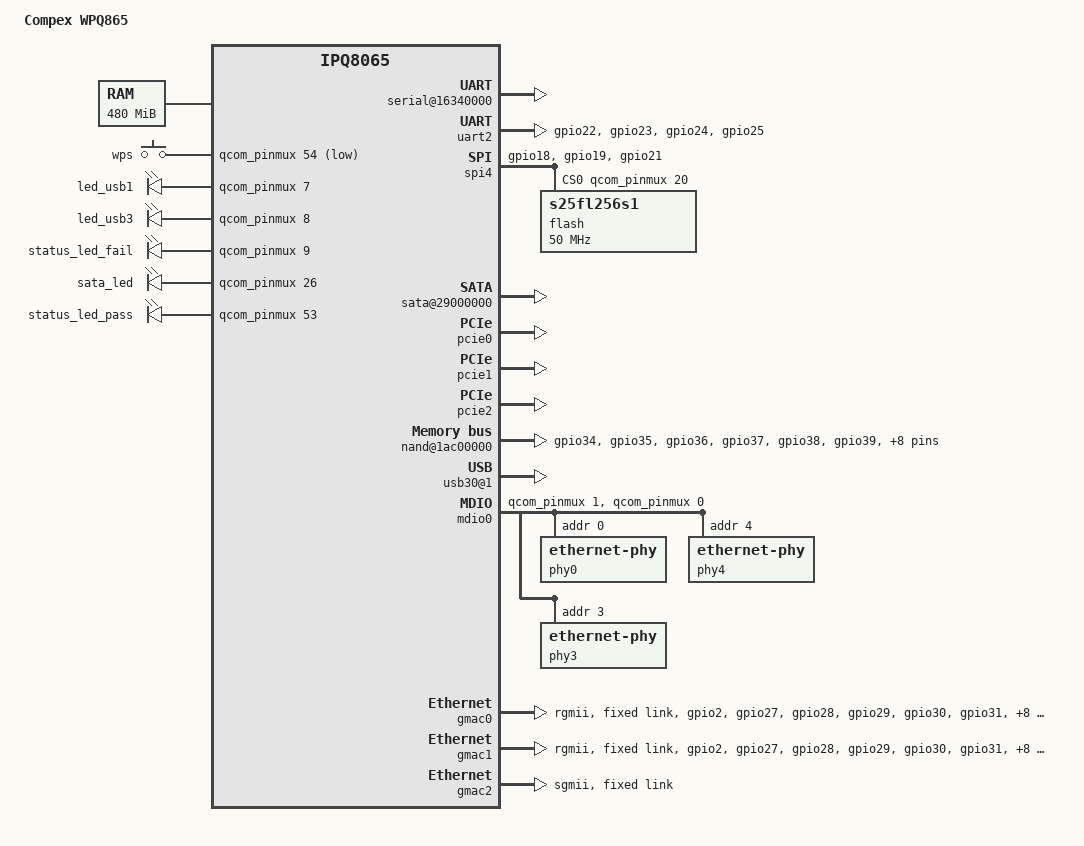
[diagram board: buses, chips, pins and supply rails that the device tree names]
/*
 *  BSD LICENSE
 *
 *  Copyright (C) 2018 Nguyen Dinh Phi <phi_nguyen@compex.com.sg>
 *  All rights reserved.
 *
 *  Redistribution and use in source and binary forms, with or without
 *  modification, are permitted provided that the following conditions
 *  are met:
 *
 *    1. Redistributions of source code must retain the above copyright
 *       notice, this list of conditions and the following disclaimer.
 *    2. Redistributions in binary form must reproduce the above copyright
 *       notice, this list of conditions and the following disclaimer in the
 *       documentation and/or other materials provided with the distribution.
 *    3. Neither the names of the copyright holders nor the names of any
 *       contributors may be used to endorse or promote products derived
 *       from this software without specific prior written permission.
 *
 *  THIS SOFTWARE IS PROVIDED BY THE COPYRIGHT HOLDERS AND CONTRIBUTORS
 *  "AS IS" AND ANY EXPRESS OR IMPLIED WARRANTIES, INCLUDING, BUT NOT
 *  LIMITED TO, THE IMPLIED WARRANTIES OF MERCHANTABILITY AND FITNESS FOR
 *  A PARTICULAR PURPOSE ARE DISCLAIMED. IN NO EVENT SHALL THE COPYRIGHT
 *  HOLDER OR CONTRIBUTORS BE LIABLE FOR ANY DIRECT, INDIRECT, INCIDENTAL,
 *  SPECIAL, EXEMPLARY, OR CONSEQUENTIAL DAMAGES (INCLUDING, BUT NOT
 *  LIMITED TO, PROCUREMENT OF SUBSTITUTE GOODS OR SERVICES; LOSS OF USE,
 *  DATA, OR PROFITS; OR BUSINESS INTERRUPTION) HOWEVER CAUSED AND ON ANY
 *  THEORY OF LIABILITY, WHETHER IN CONTRACT, STRICT LIABILITY, OR TORT
 *  (INCLUDING NEGLIGENCE OR OTHERWISE) ARISING IN ANY WAY OUT OF THE USE
 *  OF THIS SOFTWARE, EVEN IF ADVISED OF THE POSSIBILITY OF SUCH DAMAGE.
*/

#include "qcom-ipq8065-v1.0.dts"
#include <dt-bindings/input/input.h>
 /{
     model = "Compex WPQ865";
     compatible = "compex,wpq865", "qcom,ipq8065";

    aliases {
		mdio-gpio0 = &mdio0;
		/*
		 * U-Boot searches for these entries and patches
		 * 'local-mac-address'
		 */
		ethernet0 = &gmac0;
		ethernet1 = &gmac1;
		ethernet2 = &gmac2;
		serial0 = &uart4;
		serial1 = &uart2;
	};

     chosen{
         stdout-path = "serial0:115200n8"
     };

    memory@0{
        reg = <0x42000000 0x1e000000>;
        device_type = "memory";
    };

    reserved-memory{
        #address-cells = <1>;
        #size-cells = <1>;
        ranges;
        rsvd@41200000{
            reg = <0x41200000 0x300000>;
            no-map;
        };
    };

    soc{
        pinmux@800000{
            pinctrl-0 = <&rgmii2_pins>;
            pinctrl-names = "default";
            spi_pins: spi_pins{
                mux{
                    pins = "gpio18", "gpio19", "gpio21";
                    function = "gsbi5";
                    drive-strength = <10>;
                    bias-none;
                };
            };
            nand_pins: nand_pins{
                mux{
                    pins = "gpio34", "gpio35", "gpio36",
					       "gpio37", "gpio38", "gpio39",
					       "gpio40", "gpio41", "gpio42",
					       "gpio43", "gpio44", "gpio45",
					       "gpio46", "gpio47";
                    function = "nand";
                    drive-strength = <10>;
                    bias-disable;
                };
                pullups{
                    pins = "gpio39";
                    bias-pull-up;
                };
                hold{
                    pins = "gpio40", "gpio41", "gpio42",
					       "gpio43", "gpio44", "gpio45",
					       "gpio46", "gpio47";
                    bias-bus-hold;
                };
            };
            button_pins: button_pinmux{
                mux{
                    pins = "gpio54";
                    drive-strength = <2>;
                    bias-pull-up;
                };
            };

            leds_pins:leds_pinmux{
                mux{
                    pins = "gpio7", "gpio8","gpio9",
                            "gpio26", "gpio53";
                    function = "gpio";
                    drive-strength = <2>;
                    bias-pull-down;
                    output-low;
                };
            };

            hs_uart_pins: hs_uart_pins{
                mux{
                    pins = "gpio22", "gpio23", "gpio24", "gpio25";
                    function = "gsbi2";
                    drive-strength = <12>;
                    bias-disable;
                };
            };

            rgmii2_pins:rgmii2_pins{
                mux {
					pins = "gpio2", "gpio27", "gpio28",
						"gpio29", "gpio30", "gpio31",
						"gpio32", "gpio51", "gpio52",
						"gpio59", "gpio60", "gpio61",
						"gpio62","gpio66";
					function = "rgmii2";
					drive-strength = <8>;
					bias-disable;
				};
            };
        };
        /*New node for SoC*/
        gsbi@16300000{
            qcom,mode = <GSBI_PROT_I2C_UART>;
            status = "ok";
            serial@16340000{
                status = "ok";
            };
        };

        gsbi2: gsbi@12480000{
            qcom,mode = <GSBI_PROT_UART_W_FC>;
            status = "ok";
            uart2: serial@12490000{

                serial_clk = <1843200>;
                dmas = <&dma_dma 8>,
                <&adm_dma 7>;
                dma-names = "rx", "tx";
                qcom,rx-crci = <14>;
                qcom,tx-crci = <4>;

                pinctrl-0 = <&hs_uart_pins>;
                pinctrl-names = "default";

                status = "ok";
            };
        };

        gsbi5: gsbi@1a200000 {
            qcom,mode = <GSBI_PROT_SPI>;
            status = "ok";

            spi4: spi@1a280000 {
                status = "ok";
                spi-max-frequency = <50000000>;

                pinctrl-0 = <&spi_pins>;
                pinctrl-names = "default";

                cs-gpios = <&qcom_pinmux 20 0>;
                dmas = <&adm_dma 6>, <&adm_dma 5>;
                dma-names = "rx", "tx";
                qcom,rx-crci = <9>;
                qcom,tx-crci = <10>;

                flash: m25p80@0 {
                    compatible = "s25fl256s1";
                    #address-cells = <1>;
                    #size-cells = <1>;
                    spi-max-frequency = <50000000>;
                    reg = <0>;

                    m25p,fast-read;
                    partitions{
                        compatible = "fixed-partitions";
                        #address-cells = <1>;
                        #size-cells = <1>;
                    };
                };
            };
        };

        sata-phy@1b400000{
            status = "ok";
        };

        sata@29000000{
            status = "ok";
        };

        pcie0: pci@1b500000{
            status = "ok";
        };

        pcie1: pci@1b700000{
            status = "ok";
        };

        pcie2: pci@1b900000{
            status = "ok";
        };

        nand@1ac00000{
            status = "ok";

            pinctrl-0 = <&nand_pins>;
            pinctrl-names = "default";

            nand-ecc-strength = <4>;
            nand-bus-width = <8>;
        };

        phy@100f8800{
            status = "ok";
        };

        phy@100f8830{
            status = "ok";
        };

        usb30@1{
            status = "ok";
        };

        gpio_keys {
            compatible = "gpio-keys";
            pinctrl-0 = <&button_pins>;
            pinctrl-names = "default";

            button@1{
                label = "wps";
                linux,code = <KEY_WPS_BUTTON>;
                gpios = <&qcom_pinmux 54 GPIO_ACTIVE_LOW>;
                linux,input-type = <1>;
                debounce-interval = <60>;
            };
        };

        leds{
            compatible = "gpio-leds";
            pinctrl-0 = <&leds_pins>;
            pinctrl-names = "default";

            led@7 {
				label = "led_usb1";
				gpios = <&qcom_pinmux 7 GPIO_ACTIVE_HIGH>;
				linux,default-trigger = "usbdev";
				default-state = "off";
			};

			led@8 {
				label = "led_usb3";
				gpios = <&qcom_pinmux 8 GPIO_ACTIVE_HIGH>;
				linux,default-trigger = "usbdev";
				default-state = "off";
			};

			led@9 {
				label = "status_led_fail";
				gpios = <&qcom_pinmux 9 GPIO_ACTIVE_HIGH>;
				default-state = "off";
			};

			led@26 {
				label = "sata_led";
				gpios = <&qcom_pinmux 26 GPIO_ACTIVE_HIGH>;
				default-state = "off";
			};

			led@53 {
				label = "status_led_pass";
				gpios = <&qcom_pinmux 53 GPIO_ACTIVE_HIGH>;
				default-state = "off";
			};
        };

        mdio0: mdio{
            compatible = "virtual,mdio-gpio";
            #address-cells = <1>;
            #size-cells = <0>;
            gpios = <&qcom_pinmux 1 0 &qcom_pinmux 0 0>;

            phy0: ethernet-phy@0{
                device_type = "ethernet-phy";
                reg = <0>;
                qca,ar8327-initvals = <
                    0x00004 0x7600000   /* PAD0_MODE */
					0x00008 0x1000000   /* PAD5_MODE */
					0x0000c 0x20080        /* PAD6_MODE */
					0x000e4 0x6a545     /* MAC_POWER_SEL */
					0x000e0 0xc74164de  /* SGMII_CTRL */
					0x0007c 0x4e        /* PORT0_STATUS */
					0x00094 0x4e        /* PORT6_STATUS */ 
                >;
                link-polling-required = <0>;
                link-intr-gpio = <2>;
            };

            phy4: ethernet-phy@4{
                device_type = "ethernet-phy";
                reg = <4>;
                phy_rgmii_en = <1>;
                txclk_delay_en = <1>;
                rxclk_delay_en = <1>;
            };

            phy3: ethernet-phy@3{
                device_type = "ethernet-phy";
                reg = <3>;
            };
        };

        gmac0: ethernet@37000000{
            status = "ok";
            pinctrl-0 = <&rgmii2_pins>;
            pinctrl-names = "default";

            phy-mode = "rgmii";
            qcom,id = <0>;
            fixed-link {
                speed = <1000>;
                full-duplex;
            };
        };

        gmac1: ethernet@37200000{
            status = "ok";
            pinctrl-0 = <&rgmii2_pins>;
            pinctrl-names = "default";

            phy-mode = "rgmii";
            qcom,id = <1>;
            fixed-link {
                speed = <1000>;
                full-duplex;
            };
        };

        gmac2: ethernet@37400000{
            status = "ok";

            phy-mode = "sgmii";
            qcom,id = <1>;
            fixed-link {
                speed = <1000>;
                full-duplex;
        };
    };
 };

 &adm_dma {
	status = "ok";
};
